VERSION 5.8 ;
BUSBITCHARS "[]" ;
DIVIDERCHAR "/" ;
UNITS
  DATABASE MICRONS 1000 ;
END UNITS
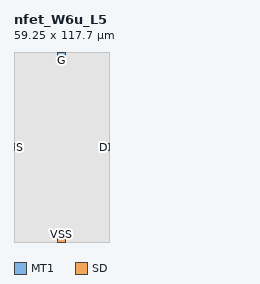
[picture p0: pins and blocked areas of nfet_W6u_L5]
MACRO nfet_W6u_L5
  CLASS BLOCK ;
  ORIGIN 0 0 ;
  FOREIGN nfet_W6u_L5 0 0 ;
  SIZE 59.25 BY 117.7 ;
  SYMMETRY X Y ;
  PIN D
    DIRECTION INOUT ;
    USE SIGNAL ;
    PORT
      LAYER MT1 ;
        RECT 56.875 56.475 59.25 61.225 ;
    END
  END D
  PIN G
    DIRECTION INPUT ;
    USE SIGNAL ;
    PORT
      LAYER MT1 ;
        RECT 27.25 115.325 32 117.7 ;
    END
  END G
  PIN S
    DIRECTION INOUT ;
    USE SIGNAL ;
    PORT
      LAYER MT1 ;
        RECT 0 56.475 2.375 61.225 ;
    END
  END S
  PIN VSS
    DIRECTION INOUT ;
    USE GROUND ;
    PORT
      LAYER SD ;
        RECT 27.25 0 32 2.375 ;
    END
  END VSS
  OBS
    LAYER SD ;
      RECT 0 0 59.25 117.7 ;
  END
END nfet_W6u_L5
END LIBRARY
